VERSION 5.7 ;
  NOWIREEXTENSIONATPIN ON ;
  DIVIDERCHAR "/" ;
  BUSBITCHARS "[]" ;
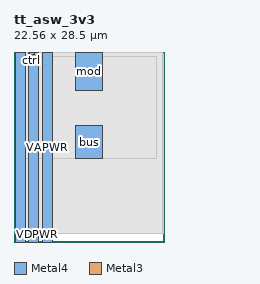
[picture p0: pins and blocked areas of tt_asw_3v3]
MACRO tt_asw_3v3
  CLASS BLOCK ;
  FOREIGN tt_asw_3v3 ;
  ORIGIN 0.000 0.000 ;
  SIZE 22.560 BY 28.500 ;
  PIN VGND
    DIRECTION INPUT ;
    USE GROUND ;
    PORT
      LAYER Metal4 ;
        RECT 2.200 0.000 3.700 28.500 ;
    END
  END VGND
  PIN VDPWR
    DIRECTION INPUT ;
    USE POWER ;
    PORT
      LAYER Metal4 ;
        RECT 0.200 0.000 1.700 28.500 ;
    END
  END VDPWR
  PIN VAPWR
    DIRECTION INPUT ;
    USE POWER ;
    PORT
      LAYER Metal4 ;
        RECT 4.200 0.000 5.700 28.500 ;
    END
  END VAPWR
  PIN ctrl
    DIRECTION INPUT ;
    USE SIGNAL ;
    ANTENNAGATEAREA 0.292500 ;
    PORT
      LAYER Metal3 ;
        RECT 2.310 28.190 3.010 28.500 ;
    END
  END ctrl
  PIN mod
    DIRECTION INOUT ;
    USE ANALOG ;
    ANTENNADIFFAREA 101.999596 ;
    PORT
      LAYER Metal4 ;
        RECT 9.280 22.790 13.280 28.500 ;
    END
  END mod
  PIN bus
    DIRECTION INOUT ;
    USE ANALOG ;
    ANTENNADIFFAREA 101.416397 ;
    PORT
      LAYER Metal4 ;
        RECT 9.280 12.500 13.280 17.500 ;
    END
  END bus
  OBS
      LAYER GatPoly ;
        RECT 0.620 1.300 22.360 28.325 ;
      LAYER Metal1 ;
        RECT 0.160 1.320 22.340 28.400 ;
      LAYER Metal2 ;
        RECT 0.200 1.325 22.335 28.400 ;
      LAYER Metal3 ;
        RECT 0.200 12.500 21.360 27.790 ;
  END
END tt_asw_3v3
END LIBRARY

